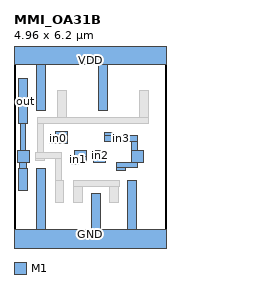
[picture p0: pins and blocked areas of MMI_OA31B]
MACRO MMI_OA31B
	CLASS CORE ;
	FOREIGN MMI_OA31B 0 0 ;
	SIZE 4.96 BY 6.2 ;
	SYMMETRY X Y ;
	SITE CORE1 ;
	PIN out
		DIRECTION output ;
		USE SIGNAL ;
		PORT
			LAYER M1 ;
			RECT 0.16 3.865 0.44 5.335 ;
			LAYER M1 ;
			RECT 0.2 2.98 0.39 3.865 ;
			LAYER M1 ;
			RECT 0.12 2.6 0.5 2.98 ;
			LAYER M1 ;
			RECT 0.175 2.385 0.415 2.6 ;
			LAYER M1 ;
			RECT 0.16 1.685 0.44 2.385 ;
		END
		AntennaDiffArea 0.91245 ;
	END out
	PIN in1
		DIRECTION input ;
		USE SIGNAL ;
		PORT
			LAYER M1 ;
			RECT 1.98 2.805 2.36 2.98 ;
			LAYER M1 ;
			RECT 1.83 2.6 2.36 2.805 ;
			LAYER M1 ;
			RECT 1.83 2.525 2.11 2.6 ;
		END
		AntennaGateArea 0.462 ;
	END in1
	PIN GND
		DIRECTION inout ;
		USE GROUND ;
		PORT
			LAYER M1 ;
			RECT 0.75 0.42 1.03 2.385 ;
			LAYER M1 ;
			RECT 2.53 0.42 2.81 1.575 ;
			LAYER M1 ;
			RECT 3.71 0.42 3.99 1.995 ;
			LAYER M1 ;
			RECT 0 -0.42 4.96 0.42 ;
		END
	END GND
	PIN in2
		DIRECTION input ;
		USE SIGNAL ;
		PORT
			LAYER M1 ;
			RECT 2.6 2.975 2.98 2.98 ;
			LAYER M1 ;
			RECT 2.6 2.695 3.03 2.975 ;
			LAYER M1 ;
			RECT 2.6 2.6 2.98 2.695 ;
		END
		AntennaGateArea 0.462 ;
	END in2
	PIN VDD
		DIRECTION inout ;
		USE POWER ;
		PORT
			LAYER M1 ;
			RECT 0 5.78 4.96 6.62 ;
			LAYER M1 ;
			RECT 0.75 4.275 1.03 5.78 ;
			LAYER M1 ;
			RECT 2.765 4.275 3.045 5.78 ;
		END
	END VDD
	PIN in3
		DIRECTION input ;
		USE SIGNAL ;
		PORT
			LAYER M1 ;
			RECT 2.96 3.475 3.24 3.565 ;
			LAYER M1 ;
			RECT 2.96 3.285 4.035 3.475 ;
			LAYER M1 ;
			RECT 3.095 3.28 4.035 3.285 ;
			LAYER M1 ;
			RECT 3.84 2.98 4.035 3.28 ;
			LAYER M1 ;
			RECT 3.84 2.605 4.22 2.98 ;
			LAYER M1 ;
			RECT 3.355 2.6 4.22 2.605 ;
			LAYER M1 ;
			RECT 3.355 2.415 4.035 2.6 ;
			LAYER M1 ;
			RECT 3.355 2.325 3.635 2.415 ;
		END
		AntennaGateArea 0.462 ;
	END in3
	PIN in0
		DIRECTION input ;
		USE SIGNAL ;
		PORT
			LAYER M1 ;
			RECT 1.36 3.51 1.74 3.6 ;
			LAYER M1 ;
			RECT 1.155 3.23 1.74 3.51 ;
			LAYER M1 ;
			RECT 1.36 3.22 1.74 3.23 ;
		END
		AntennaGateArea 0.231 ;
	END in0
	OBS
		LAYER M1 ;
		RECT 1.435 4.055 1.715 4.95 ;
		LAYER M1 ;
		RECT 4.095 4.055 4.375 4.95 ;
		LAYER M1 ;
		RECT 0.755 3.865 4.375 4.055 ;
		LAYER M1 ;
		RECT 0.755 2.93 0.95 3.865 ;
		LAYER M1 ;
		RECT 0.705 2.735 1.55 2.93 ;
		LAYER M1 ;
		RECT 0.705 2.65 0.985 2.735 ;
		LAYER M1 ;
		RECT 1.355 1.995 1.55 2.735 ;
		LAYER M1 ;
		RECT 1.945 1.995 3.435 2 ;
		LAYER M1 ;
		RECT 1.35 1.295 1.63 1.995 ;
		LAYER M1 ;
		RECT 1.94 1.805 3.435 1.995 ;
		LAYER M1 ;
		RECT 1.94 1.295 2.22 1.805 ;
		LAYER M1 ;
		RECT 3.12 1.295 3.4 1.805 ;
	END
END MMI_OA31B
